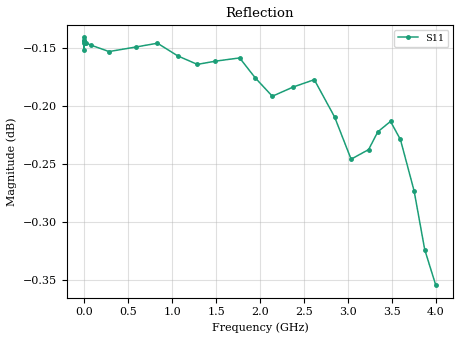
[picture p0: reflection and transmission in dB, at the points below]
#  HZ  Z  MA  R  50.0
! Rohde & Schwarz ZVL
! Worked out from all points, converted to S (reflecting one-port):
!   1001 points, 100 kHz to 4 GHz, reference 50 ohm
!   lowest |S11| = -0.4 dB at 4 GHz (marker M1), VSWR 49.06, Z = 803 - j1.15e+03 ohm
!   phase of S11 starts at -0 deg and turns -3 deg over the sweep
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100000  120.2 -2.0
376060.3  114.1 -2.5
625397.8  123.2 -0.6
702714.7  118.9 0.0
1414214  121.6 -0.4
5318296  119.4 -0.2
2e7  119.3 -0.9
7.521206e7  117.5 -3.2
2.828427e8  112.3 -8.0
5.876072e8  112.3 -15.2
8.33595e8  107.3 -25.6
1.063659e9  94.22 -31.7
1.287181e9  89.21 -32.5
1.49303e9  86.04 -36.9
1.768892e9  76.47 -45.7
1.945897e9  67.52 -46.9
2.140614e9  63.31 -45.7
2.379902e9  62.06 -49.0
2.618048e9  54.9 -55.9
2.849667e9  45.5 -56.7
3.036732e9  42.13 -53.4
3.236077e9  42.46 -54.5
3.340604e9  41.64 -57.8
3.485244e9  38.35 -61.9
3.59782e9  34.21 -63.2
3.753597e9  29.85 -62.0
3.87484e9  27.78 -58.8
4e9  28.05 -55.1
